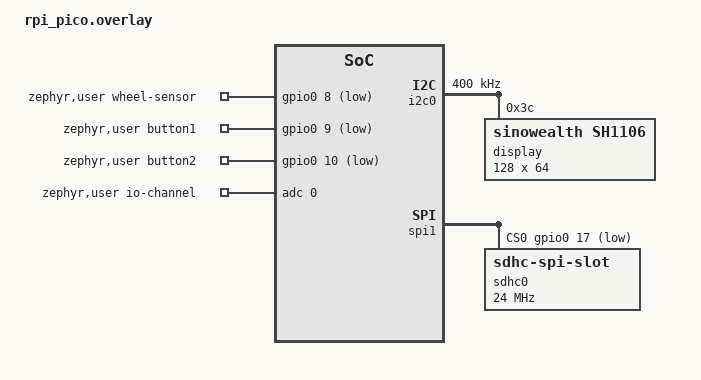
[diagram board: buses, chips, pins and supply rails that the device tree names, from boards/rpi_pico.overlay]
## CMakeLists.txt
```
cmake_minimum_required(VERSION 3.20.0)

find_package(Zephyr REQUIRED HINTS $ENV{ZEPHYR_BASE})
project(wheel_sensor)

# Include directories
target_include_directories(app PRIVATE include src)

# Main application and module sources
target_sources(app PRIVATE
    src/main.c
    src/app.c
    src/wheel_sensor.c
    src/button.c
    src/battery.c
    src/speed_calculator.c
    src/display_output.c
    src/console_output.c
    src/storage.c
)

# Simulation shell (optional)
if(CONFIG_APP_SIMULATION)
    target_sources(app PRIVATE src/sim_shell.c)
endif()
```

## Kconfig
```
menu "Application Configuration"

config DISPLAY_ENABLED
	bool "Enable OLED display support (SH1106)"
	default y
	imply I2C
	imply DISPLAY
	imply SSD1306
	imply CHARACTER_FRAMEBUFFER
	help
		Enable support for SH1106 OLED display over I2C.
		When enabled, the display driver and related functionality are included.
		When disabled, all display-related code is excluded.

config SD_CARD_ENABLED
	bool "Enable SD card storage via SPI"
	default y
	imply SPI
	imply SDHC
	imply SDMMC_STACK
	imply DISK_ACCESS
	imply FILE_SYSTEM
	imply FAT_FILESYSTEM_ELM
	help
		Enable support for SD card storage over SPI.
		When enabled, the SD card driver and filesystem support are included.
		When disabled, all SD card-related code and dependencies are excluded.

config APP_SIMULATION
    bool "Enable shell commands to drive simulated peripherals"
    depends on GPIO_EMUL || ADC_EMUL
    help
      Adds 'sim' shell commands to manually toggle the reed switch,
      simulate a button press, and set a fake battery voltage while
      running the app on native_sim.

config LOG_LEVEL_GLOBAL
	int "Global application log level"
	default 3
	range 0 4
	help
		Sets the default log level for all application modules.
		0 - None, 1 - Error, 2 - Warning, 3 - Info, 4 - Debug
		Individual modules can still use LOG_LEVEL_SET() to override.

endmenu

source "Kconfig.zephyr"
```

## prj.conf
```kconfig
# GPIO is required to read the reed switch / Hall sensor
CONFIG_GPIO=y

# ADC for battery voltage monitoring
CONFIG_ADC=y

# Console output so we can see revolution/speed data over USB-UART
CONFIG_PRINTK=y
CONFIG_CONSOLE=y
CONFIG_SERIAL=y

# SPI for SD card (enabled by SD_CARD_ENABLED config)
CONFIG_EMUL=y
CONFIG_HEAP_MEM_POOL_SIZE=256

# Settings subsystem for persistent storage
CONFIG_SETTINGS=y
CONFIG_SETTINGS_RUNTIME=y
CONFIG_FLASH=y
CONFIG_FLASH_MAP=y
CONFIG_NVS=y

# Logging configuration
CONFIG_LOG=y
```

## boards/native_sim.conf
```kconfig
CONFIG_GPIO=y
CONFIG_GPIO_EMUL=y
CONFIG_ADC=y
CONFIG_ADC_EMUL=y
CONFIG_CONSOLE=y
CONFIG_SHELL=y
CONFIG_SHELL_BACKEND_SERIAL=y

# Disable display support for native_sim
CONFIG_DISPLAY_ENABLED=n
CONFIG_DISPLAY=n

CONFIG_APP_SIMULATION=y
```

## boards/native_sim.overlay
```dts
/*
 * Simulation overlay mapping to the same paths as rpi_pico.overlay
 * Uses zephyr,user node with the same property names
 */
/ {
	zephyr,user {
		/* Wheel sensor - maps to reed0 in sim_inputs */
		wheel-sensor-gpios = <&gpio0 1 (GPIO_ACTIVE_LOW)>;
		/* Buttons - map to button0 in sim_inputs */
		button1-gpios = <&gpio0 0 (GPIO_ACTIVE_LOW)>;
		button2-gpios = <&gpio0 2 (GPIO_ACTIVE_LOW)>;
		/* Battery ADC channel - maps to channel@0 in adc0 */
		io-channels = <&adc0 0>;
	};
};

/* native_sim.dts already provides gpio0 as a gpio_emul controller
   and usually an adc0 as zephyr,adc-emul — check your Zephyr version's
   boards/native/native_sim/native_sim.dts. If adc0 isn't already there,
   add it yourself here instead of just configuring the channel below. */
&adc0 {
	#address-cells = <1>;
	#size-cells = <0>;

	channel@0 {
		reg = <0>;
		zephyr,gain = "ADC_GAIN_1";
		zephyr,reference = "ADC_REF_INTERNAL";
		zephyr,vref-mv = <3300>;
		zephyr,resolution = <12>;
		zephyr,acquisition-time = <ADC_ACQ_TIME_DEFAULT>;
	};
};
```

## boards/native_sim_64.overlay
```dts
/*
 * native_sim 64-bit variant overlay.
 * Keep the native simulator free of display emulation and provide the
 * same user-facing GPIO and ADC nodes the application expects.
 */
/ {
	zephyr,user {
		/* Wheel sensor - maps to reed0 in sim_inputs */
		wheel-sensor-gpios = <&gpio0 1 (GPIO_ACTIVE_LOW)>;
		/* Buttons - map to button0 in sim_inputs */
		button1-gpios = <&gpio0 0 (GPIO_ACTIVE_LOW)>;
		button2-gpios = <&gpio0 2 (GPIO_ACTIVE_LOW)>;
		/* Battery ADC channel - maps to channel@0 in adc0 */
		io-channels = <&adc0 0>;
	};

	chosen {
		/delete-property/ zephyr,display;
	};
};

&sdl_dc {
	status = "disabled";
};

&spi0 {
	sdhc0: sdhc@0 {
		compatible = "zephyr,sdhc-spi-slot";
		reg = <0>;
		status = "okay";
		spi-max-frequency = <24000000>;

		mmc {
			compatible = "zephyr,sdmmc-disk";
			disk-name = "SD";
			status = "okay";
		};
	};
};

&adc0 {
	#address-cells = <1>;
	#size-cells = <0>;

	channel@0 {
		reg = <0>;
		zephyr,gain = "ADC_GAIN_1";
		zephyr,reference = "ADC_REF_INTERNAL";
		zephyr,vref-mv = <3300>;
		zephyr,resolution = <12>;
		zephyr,acquisition-time = <ADC_ACQ_TIME_DEFAULT>;
	};
};
```

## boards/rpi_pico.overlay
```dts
/*
 * Wire the reed switch / Hall sensor to GPIO pin 16.
 * One leg of the switch/sensor goes to this pin, the other to GND.
 * GPIO_PULL_UP keeps the line high when open; the switch/sensor pulls
 * it low (ACTIVE_LOW) when the magnet passes.
 *
 * Change the pin number below to match your wiring if needed.
 */
/ {
	zephyr,user {
		wheel-sensor-gpios = <&gpio0 8 (GPIO_ACTIVE_LOW | GPIO_PULL_UP)>;
		button1-gpios = <&gpio0 9 (GPIO_ACTIVE_LOW | GPIO_PULL_UP)>;
		button2-gpios = <&gpio0 10 (GPIO_ACTIVE_LOW | GPIO_PULL_UP)>;
		/* Battery voltage monitoring via ADC0 (GPIO26) */
		io-channels = <&adc 0>;
	};

	chosen {
		zephyr,display = &display;
	};
};

/* Enable I2C for SH1106 display */
&i2c0 {
	status = "okay";
	clock-frequency = <400000>;

	display: sh1106@3c {
		compatible = "sinowealth,sh1106";
		reg = <0x3c>;
		width = <128>;
		height = <64>;
		segment-offset = <0>;
		page-offset = <0>;
		display-offset = <0>;
		multiplex-ratio = <63>;
		segment-remap;
		com-invdir;
		prechargep = <0x22>;
	};
};

/* Add storage partition for NVS settings to existing flash0 partitions */
&flash0 {
	partitions {
		compatible = "fixed-partitions";
        #address-cells = <1>;
        #size-cells = <1>;
			/* Storage partition for NVS settings - 16KB at 128KB offset from flash start */
		storage_partition: partition@20000 {
			label = "storage";
			reg = <0x00020000 0x00004000>;
		};
	};
};

&spi1 {
        status = "okay";
        cs-gpios = <&gpio0 17 GPIO_ACTIVE_LOW>;

        sdhc0: sdhc@0 {
                compatible = "zephyr,sdhc-spi-slot";
                reg = <0>;
                status = "okay";
                mmc {
                    compatible = "zephyr,sdmmc-disk";
                    disk-name = "SD";
                    status = "okay";
                };
                spi-max-frequency = <24000000>;
        };
};
```

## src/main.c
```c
/*
 * main.c - Application entry point
 *
 * Simply calls the modular application implementation.
 *
 * @implements REQ-SW-001
 */

#include <app.h>

/**
 * @brief Application main entry point
 * @implements REQ-SW-001
 * @return Application exit code
 */
int main(void)
{
	return app_run();
}
```

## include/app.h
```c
/*
 * app.h - Main application header for wheel sensor speedometer
 *
 * Defines shared data structures, constants, and constants.
 * All modules should include this header for common types.
 *
 * Module-specific interfaces are in their respective header files:
 * - wheel_sensor.h
 * - button.h
 * - battery.h
 * - speed_calculator.h
 * - display_output.h
 * - console_output.h
 * - storage.h
 */

#ifndef APP_H
#define APP_H

#include <zephyr/kernel.h>
#include <zephyr/sys/atomic.h>
#include <stdbool.h>
#include <stdint.h>

/* =========================================================================
 * CONSTANTS
 * ========================================================================= */

/* Wheel configuration limits */
#define MIN_WHEEL_DIAMETER_CM    10
#define MAX_WHEEL_DIAMETER_CM    100
#define DEFAULT_WHEEL_DIAMETER_CM 66

/* Timing constants */
#define DEBOUNCE_MS              50
#define REPORT_INTERVAL_MS       1000
#define MODE_SWITCH_DELAY_MS     500
#define BATTERY_SAMPLE_INTERVAL_S 60

/* Battery monitoring constants */
#define BATTERY_MIN_V            2.0f   /* Voltage at 0% (2x AA depleted) */
#define BATTERY_MAX_V            3.0f   /* Voltage at 100% (2x AA fresh) */
#define VOLTAGE_DIVIDER_RATIO    (3.0f / 2.0f)  /* V_battery = V_adc * (R1+R2)/R2 */

/* Buffer sizes */
#define LOG_BUFFER_SIZE          256
#define DISPLAY_LINE_SIZE        32

/* =========================================================================
 * DATA STRUCTURES
 * ========================================================================= */

/* Wheel sensor state - shared between ISR and main thread */
struct wheel_sensor_state {
	atomic_t revolution_count;
	volatile int64_t last_trigger_ms;
};

/* Button state - shared between ISR and main thread */
struct button_state {
	volatile int64_t last_press_ms[2];
	volatile bool in_settings_mode;
	volatile bool save_wheel_diameter_pending;
	int64_t previous_press_time[2];
	/* Flags for deferred printing (set in ISR, cleared in main thread) */
	volatile bool settings_mode_changed;
	volatile bool diameter_changed;
	int diameter_value;
};

/* Wheel configuration */
struct wheel_config {
	int diameter_cm;
};

/* Battery state */
struct battery_state {
	int percentage;
	float voltage;
	bool valid;
};

/* Runtime tracking state (main thread only) */
struct runtime_state {
	uint32_t last_count;
	uint32_t total_distance_m;
	float last_speed_kmh;
};

/* =========================================================================
 * INLINE ACCESSORS
 * ========================================================================= */

/**
 * @brief Check if in settings mode
 * @param button_state Pointer to button state structure
 * @return true if in settings mode
 */
static inline bool button_in_settings_mode(const struct button_state *button_state)
{
	return button_state->in_settings_mode;
}

/**
 * @brief Check if wheel diameter needs saving
 * @param button_state Pointer to button state structure
 * @return true if pending save
 */
static inline bool button_save_pending(const struct button_state *button_state)
{
	return button_state->save_wheel_diameter_pending;
}

/**
 * @brief Clear save pending flag
 * @param button_state Pointer to button state structure
 */
static inline void button_clear_save_pending(struct button_state *button_state)
{
	button_state->save_wheel_diameter_pending = false;
}

/**
 * @brief Application entry point
 */
int app_run(void);

#endif /* APP_H */
```

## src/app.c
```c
/*
 * app.c - Main application with modular architecture
 *
 * Coordinates all modules to implement the wheel sensor speedometer.
 *
 * @implements REQ-SW-001, REQ-SW-002, REQ-SW-003, REQ-SW-004, REQ-SW-005, REQ-SW-006, REQ-SW-007, REQ-SW-008
 */

#include <app.h>
#include <wheel_sensor.h>
#include <button.h>
#include <battery.h>
#include <speed_calculator.h>
#include <display_output.h>
#include <console_output.h>
#include <storage.h>

#include <zephyr/kernel.h>
#include <zephyr/sys/printk.h>
#include <zephyr/sys/util.h>
#include <zephyr/logging/log.h>

LOG_MODULE_REGISTER(app);

/* Global state instances */
static struct wheel_sensor_state wheel_sensor_state = {
	.revolution_count = ATOMIC_INIT(0),
	.last_trigger_ms = 0,
};

static struct button_state button_state = {
	.last_press_ms = {0, 0},
	.in_settings_mode = false,
	.save_wheel_diameter_pending = false,
	.previous_press_time = {0, 0},
	.settings_mode_changed = false,
	.diameter_changed = false,
	.diameter_value = DEFAULT_WHEEL_DIAMETER_CM,
};

static struct wheel_config wheel_config = {
	.diameter_cm = DEFAULT_WHEEL_DIAMETER_CM,
};

static struct runtime_state runtime_state = {
	.last_count = 0U,
	.total_distance_m = 0U,
	.last_speed_kmh = 0.0f,
};

static struct battery_state battery_state = {
	.percentage = -1,
	.voltage = 0.0f,
	.valid = false,
};

static void app_state_work_handler(struct k_work *work);

K_WORK_DEFINE(app_state_work, app_state_work_handler);

/**
 * @brief Work handler for deferred state updates
 * @implements REQ-SW-003, REQ-SW-601
 * @param work Work item (unused)
 */
static void app_state_work_handler(struct k_work *work)
{
	ARG_UNUSED(work);

	if (button_save_pending(&button_state)) {
		button_clear_save_pending(&button_state);
		storage_save_wheel_diameter(&wheel_config);
	}

	if (display_is_available()) {
		display_render(&button_state, &wheel_config, &runtime_state, &battery_state);
	}
}

/**
 * @brief Queue deferred state update
 * @implements REQ-SW-601
 */
static void queue_app_state_update(void)
{
	k_work_submit(&app_state_work);
}

/**
 * @brief Main application entry point
 * @implements REQ-SW-001, REQ-SW-002, REQ-SW-003, REQ-SW-004, REQ-SW-005, REQ-SW-006, REQ-SW-007, REQ-SW-008
 * @return Application exit code
 */
int app_run(void)
{
	int ret;

	/* Initialize storage/NVS first so settings can be loaded */
	ret = storage_init(&wheel_config);
	if (ret < 0) {
		LOG_ERR("Storage initialization failed: %d", -ret);
		return ret;
	}

	console_print_init(wheel_config.diameter_cm);

	/* Initialize display */
	ret = display_init();
	if (ret < 0) {
		LOG_WRN("Display initialization failed: %d, continuing without display", -ret);
	} else {
		queue_app_state_update();
	}

	/* Initialize SD card for logging */
	ret = storage_sd_init();
	if (ret < 0) {
		LOG_WRN("SD card initialization failed: %d, continuing without SD card", -ret);
	} else {
		ret = storage_log_open();
		if (ret < 0) {
			LOG_WRN("Failed to open log file: %d, continuing without SD card logging", -ret);
		} else {
			LOG_INF("SD card logging initialized");
		}
	}

	/* Initialize battery monitoring */
	ret = battery_init();
	if (ret < 0) {
		LOG_ERR("Battery initialization failed: %d", -ret);
		return ret;
	}

	/* Initialize wheel sensor */
	ret = wheel_sensor_init(&wheel_sensor_state);
	if (ret < 0) {
		LOG_ERR("Wheel sensor initialization failed: %d", -ret);
		return ret;
	}

	/* Initialize buttons */
	button_set_wheel_config(&wheel_config);
	ret = button_init(&button_state);
	if (ret < 0) {
		LOG_WRN("Button initialization failed: %d, continuing without buttons", -ret);
	}

	uint32_t battery_sample_counter = 0;

	while (1) {
		k_msleep(REPORT_INTERVAL_MS);

		/* Sample battery voltage periodically */
		battery_sample_counter++;
		if (battery_sample_counter >= BATTERY_SAMPLE_INTERVAL_S) {
			int battery_ret = battery_read(&battery_state);
			if (battery_ret < 0) {
				LOG_ERR("Battery read failed: %d", battery_ret);
			} else {
				console_print_battery(battery_state.percentage, battery_state.voltage);
			}
			battery_sample_counter = 0;
		}

		/* Handle deferred button press messages (from ISR) */
		if (button_state.settings_mode_changed) {
			button_state.settings_mode_changed = false;
			if (button_state.in_settings_mode) {
				LOG_INF("Entering settings mode. Current diameter: %d cm",
					button_state.diameter_value);
			} else {
				LOG_INF("Exiting settings mode. Wheel diameter set to: %d cm",
					button_state.diameter_value);
			}
		}
		if (button_state.diameter_changed) {
			button_state.diameter_changed = false;
			LOG_INF("Wheel diameter: %d cm", button_state.diameter_value);
		}

		/* If in settings mode, skip speed calculation but still update display */
		if (button_in_settings_mode(&button_state)) {
			queue_app_state_update();
			continue;
		}

		/* Get current revolution count */
		uint32_t current_count = wheel_sensor_get_count(&wheel_sensor_state);

		/* Calculate speed and distance */
		speed_calculator_update(
			current_count, runtime_state.last_count,
			wheel_config.diameter_cm, REPORT_INTERVAL_MS,
			&runtime_state.total_distance_m, &runtime_state.last_speed_kmh);
		runtime_state.last_count = current_count;

		/* Print status to console */
		console_print_status(
			current_count, runtime_state.last_speed_kmh,
			runtime_state.total_distance_m, wheel_config.diameter_cm);

		/* Log to SD card if available */
		if (storage_log_available()) {
			char log_msg[LOG_BUFFER_SIZE];
			snprintk(log_msg, sizeof(log_msg),
				"[%lld] revs=%u, speed=%.1f km/h, distance=%u m, diameter=%d cm\n",
				k_uptime_get(), current_count, (double)runtime_state.last_speed_kmh,
				runtime_state.total_distance_m, wheel_config.diameter_cm);
			storage_log_write(log_msg);
		}

		queue_app_state_update();
	}

	return 0;
}
```

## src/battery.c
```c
/*
 * battery.c - Battery monitoring module
 *
 * Handles ADC-based battery voltage monitoring and percentage calculation.
 *
 * @implements REQ-HW-040, REQ-HW-041, REQ-HW-042, REQ-SW-401, REQ-SW-402, REQ-SW-403, REQ-SW-404, REQ-SW-405, REQ-SW-406, REQ-SW-407, REQ-SW-408, REQ-SW-409, REQ-SW-410
 * @tests tests/battery/src/test_battery.c
 */

#include <battery.h>
#include <zephyr/kernel.h>
#include <zephyr/drivers/adc.h>
#include <zephyr/logging/log.h>

LOG_MODULE_REGISTER(battery);

/* Devicetree configuration */
#define USER_NODE DT_PATH(zephyr_user)
static const struct adc_dt_spec battery_adc =
	ADC_DT_SPEC_GET_BY_IDX(USER_NODE, 0);

/**
 * @brief Initialize battery ADC
 * @implements REQ-SW-401
 * @return 0 on success, negative errno on failure
 */
int battery_init(void)
{
	if (!device_is_ready(battery_adc.dev)) {
		return -ENODEV;
	}
	return 0;
}

/**
 * @brief Read battery voltage and update state
 *
 * Battery must be already initialized via a successful call to
 * battery_init() prior to calling this function.
 *
 * @implements REQ-SW-401, REQ-SW-402, REQ-SW-410
 * @param battery_state Pointer to battery state structure to update
 * @return 0 on success, negative errno on failure
 */
int battery_read(struct battery_state *battery_state)
{
	int16_t adc_value;
	struct adc_sequence sequence = {
		.channels = BIT(battery_adc.channel_id),
		.buffer = &adc_value,
		.buffer_size = sizeof(adc_value),
		.resolution = 12,
	};

	int ret = adc_read(battery_adc.dev, &sequence);
	if (ret < 0) {
		LOG_ERR("Battery ADC read error: %d", ret);
		return ret;
	}

	float battery_voltage = battery_adc_to_voltage(adc_value);
	int percentage = battery_voltage_to_percentage(battery_voltage);

	battery_state->voltage = battery_voltage;
	battery_state->percentage = percentage;
	battery_state->valid = true;

	return 0;
}

/**
 * @brief Convert ADC value to battery voltage
 * @implements REQ-SW-403, REQ-SW-404, REQ-SW-405
 * @param adc_value Raw ADC value (12-bit)
 * @return Battery voltage in volts
 */
float battery_adc_to_voltage(int16_t adc_value)
{
	/* Convert ADC value to voltage (12-bit ADC, 3.3V reference)
	 * NOTE: The 3.3V reference is hardcoded. The actual RP2040 ADC reference
	 * can vary by +/- 1-2% which will cause a systematic offset in battery
	 * voltage readings. For more accurate readings, consider reading the
	 * actual Vref from ADC calibration data. */
	float adc_voltage = (adc_value * 3.3f) / 4095.0f;

	/* Apply voltage divider ratio: V_battery = V_adc * (R1+R2)/R2 */
	return adc_voltage * VOLTAGE_DIVIDER_RATIO;
}

/**
 * @brief Convert battery voltage to percentage
 * @implements REQ-SW-406, REQ-SW-407, REQ-SW-408, REQ-SW-409
 * @param voltage Battery voltage in volts
 * @return Percentage (0-100)
 */
int battery_voltage_to_percentage(float voltage)
{
	/* Linear approximation for alkaline 2xAA */
	int percentage = (int)((voltage - BATTERY_MIN_V) /
			(BATTERY_MAX_V - BATTERY_MIN_V) * 100.0f);
	return CLAMP(percentage, 0, 100);
}
```

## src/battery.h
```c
/*
 * battery.h - Battery monitoring module interface
 *
 * Handles ADC-based battery voltage monitoring and percentage calculation.
 */

#ifndef BATTERY_H
#define BATTERY_H

#include "app.h"
#include <zephyr/device.h>
#include <zephyr/devicetree.h>
#include <zephyr/drivers/adc.h>
#include <stdbool.h>

/**
 * @brief Initialize battery ADC
 * @return 0 on success, negative errno on failure
 */
__must_check int battery_init(void);

/**
 * @brief Read battery voltage and update state
 * @param battery_state Pointer to battery state structure to update
 * @return 0 on success, negative errno on failure
 */
__must_check int battery_read(struct battery_state *battery_state);

/**
 * @brief Convert ADC value to battery voltage
 * @param adc_value Raw ADC value (12-bit)
 * @return Battery voltage in volts
 */
float battery_adc_to_voltage(int16_t adc_value);

/**
 * @brief Convert battery voltage to percentage
 * @param voltage Battery voltage in volts
 * @return Percentage (0-100)
 */
int battery_voltage_to_percentage(float voltage);

#endif /* BATTERY_H */
```

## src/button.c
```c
/*
 * button.c - Button input module
 *
 * Handles button input with debouncing and settings mode management.
 * Button 1: Double-press toggles settings mode, single press increments diameter
 * Button 2: Single press decrements diameter in settings mode
 *
 * @implements REQ-HW-020, REQ-HW-021, REQ-HW-022, REQ-HW-023, REQ-SW-301, REQ-SW-302, REQ-SW-303, REQ-SW-304, REQ-SW-305, REQ-SW-306, REQ-SW-307, REQ-SW-308, REQ-SW-309, REQ-SW-310, REQ-SW-311
 */

#include <button.h>
#include <app.h>
#include <zephyr/kernel.h>
#include <zephyr/drivers/gpio.h>
#include <zephyr/sys/printk.h>
#include <zephyr/sys/util.h>
#include <zephyr/sys/check.h>

/* Devicetree configuration */
#define USER_NODE DT_PATH(zephyr_user)
static const struct gpio_dt_spec button1 =
	GPIO_DT_SPEC_GET(USER_NODE, button1_gpios);
static const struct gpio_dt_spec button2 =
	GPIO_DT_SPEC_GET(USER_NODE, button2_gpios);

static struct button_state *button_state_ptr = NULL;
static struct wheel_config *wheel_config_ptr = NULL;

/* NOTE: button_state_ptr and wheel_config_ptr are set by button_init() and
 * button_set_wheel_config() respectively. There is a small race condition window
 * between these two calls in app.c where button_set_wheel_config() is called
 * before button_init(). If a button interrupt fires during this window,
 * __ASSERT_NO_MSG(wheel_config_ptr != NULL) will trigger. In practice this is
 * unlikely as initialization is fast, but for robustness consider using a
 * single initialization function that takes all required pointers. */

/* Button callback data structure with user data */
struct button_cb_data {
	struct gpio_callback callback;
	int button_idx;
};
static struct button_cb_data button_cb_data[2];

/* Internal processing function */
/**
 * @brief Internal processing function for button presses
 * @implements REQ-SW-301, REQ-SW-302, REQ-SW-303, REQ-SW-304, REQ-SW-305, REQ-SW-306, REQ-SW-307, REQ-SW-308, REQ-SW-309, REQ-SW-310, REQ-SW-311
 * @param button_idx Button index (0 for button1, 1 for button2)
 */
static void process_button_press(int button_idx)
{
	/* Use __ASSERT_NO_MSG for NULL checks in ISR context */
	__ASSERT_NO_MSG(button_state_ptr != NULL);
	__ASSERT_NO_MSG(wheel_config_ptr != NULL);

	int64_t now = k_uptime_get();

	/* Debounce check */
	if ((now - button_state_ptr->last_press_ms[button_idx]) < DEBOUNCE_MS) {
		return;
	}
	button_state_ptr->last_press_ms[button_idx] = now;

	if (button_idx == 0) {
		/* Button 1: double press toggles settings mode; single press increments diameter */
		if ((now - button_state_ptr->previous_press_time[button_idx]) < MODE_SWITCH_DELAY_MS) {
			button_state_ptr->in_settings_mode = !button_state_ptr->in_settings_mode;
			button_state_ptr->settings_mode_changed = true;
			button_state_ptr->diameter_value = wheel_config_ptr->diameter_cm;
			if (!button_state_ptr->in_settings_mode) {
				button_state_ptr->save_wheel_diameter_pending = true;
			}
		} else {
			if (button_state_ptr->in_settings_mode) {
				wheel_config_ptr->diameter_cm =
					MIN(wheel_config_ptr->diameter_cm + 1, MAX_WHEEL_DIAMETER_CM);
				button_state_ptr->diameter_changed = true;
				button_state_ptr->diameter_value = wheel_config_ptr->diameter_cm;
			}
		}
		button_state_ptr->previous_press_time[button_idx] = now;
	} else {
		/* Button 2: single press decrements diameter in settings mode */
		if (button_state_ptr->in_settings_mode) {
			wheel_config_ptr->diameter_cm =
				MAX(wheel_config_ptr->diameter_cm - 1, MIN_WHEEL_DIAMETER_CM);
			button_state_ptr->diameter_changed = true;
			button_state_ptr->diameter_value = wheel_config_ptr->diameter_cm;
		}
	}
}

/**
 * @brief Unified callback for all buttons
 * @implements REQ-SW-301, REQ-SW-302
 * @param dev Device pointer (unused)
 * @param cb Callback pointer
 * @param pins Triggered pins (unused)
 */
/* Unified callback for all buttons */
static void button_pressed(const struct device *dev, struct gpio_callback *cb, uint32_t pins)
{
	ARG_UNUSED(dev);
	ARG_UNUSED(pins);
	struct button_cb_data *data = CONTAINER_OF(cb, struct button_cb_data, callback);
	process_button_press(data->button_idx);
}

/**
 * @brief Initialize button GPIOs and interrupts
 * @implements REQ-SW-301, REQ-SW-302
 * @param button_state Pointer to button state structure
 * @return 0 on success, negative errno on failure
 */
int button_init(struct button_state *button_state)
{
	int ret;

	button_state_ptr = button_state;

	/* Initialize button state */
	button_state->last_press_ms[0] = 0;
	button_state->last_press_ms[1] = 0;
	button_state->in_settings_mode = false;
	button_state->save_wheel_diameter_pending = false;
	button_state->previous_press_time[0] = 0;
	button_state->previous_press_time[1] = 0;

	if (!device_is_ready(button1.port) || !device_is_ready(button2.port)) {
		return -ENODEV;
	}

	/* Configure button 1 */
	ret = gpio_pin_configure_dt(&button1, GPIO_INPUT);
	if (ret != 0) {
		return ret;
	}

	ret = gpio_pin_interrupt_configure_dt(&button1, GPIO_INT_EDGE_TO_ACTIVE);
	if (ret != 0) {
		return ret;
	}

	button_cb_data[0].button_idx = 0;
	gpio_init_callback(&button_cb_data[0].callback, button_pressed, BIT(button1.pin));
	gpio_add_callback(button1.port, &button_cb_data[0].callback);

	/* Configure button 2 */
	ret = gpio_pin_configure_dt(&button2, GPIO_INPUT);
	if (ret != 0) {
		return ret;
	}

	ret = gpio_pin_interrupt_configure_dt(&button2, GPIO_INT_EDGE_TO_ACTIVE);
	if (ret != 0) {
		return ret;
	}

	button_cb_data[1].button_idx = 1;
	gpio_init_callback(&button_cb_data[1].callback, button_pressed, BIT(button2.pin));
	gpio_add_callback(button2.port, &button_cb_data[1].callback);

	return 0;
}

/**
 * @brief Set wheel config pointer for button callbacks
 * @implements REQ-SW-303
 * @param wheel_config Pointer to wheel configuration
 */
void button_set_wheel_config(struct wheel_config *wheel_config)
{
	wheel_config_ptr = wheel_config;
}
```

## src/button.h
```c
/*
 * button.h - Button input module interface
 *
 * Handles button input with debouncing and settings mode management.
 */

#ifndef BUTTON_H
#define BUTTON_H

#include <app.h>
#include <zephyr/device.h>
#include <zephyr/devicetree.h>
#include <zephyr/drivers/gpio.h>

/**
 * @brief Initialize button GPIOs and interrupts
 * @param button_state Pointer to button state structure
 * @return 0 on success, negative errno on failure
 */
int button_init(struct button_state *button_state);

/**
 * @brief Set wheel config pointer for button callbacks
 * @param wheel_config Pointer to wheel configuration
 */
void button_set_wheel_config(struct wheel_config *wheel_config);

/**
 * @brief Get button count
 * @return Number of buttons (currently 2)
 */
static inline int button_count(void)
{
	return 2;
}

#endif /* BUTTON_H */
```

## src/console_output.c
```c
/*
 * console_output.c - Console output module
 *
 * Handles all console/printk output for the application.
 *
 * @implements REQ-SW-701, REQ-SW-702, REQ-SW-703, REQ-SW-704, REQ-SW-705, REQ-SW-706, REQ-SW-707, REQ-SW-708
 */

#include <console_output.h>
#include <zephyr/sys/printk.h>
#include <zephyr/logging/log.h>

LOG_MODULE_REGISTER(console);

/**
 * @brief Print status information to console
 * @implements REQ-SW-701, REQ-SW-702
 * @param current_count Current revolution count
 * @param speed_kmh Current speed in km/h
 * @param total_distance_m Total distance in meters
 * @param wheel_diameter_cm Wheel diameter in centimeters
 */
void console_print_status(uint32_t current_count, float speed_kmh,
		uint32_t total_distance_m, int wheel_diameter_cm)
{
	unsigned int speed_frac = (unsigned int)((speed_kmh - (int)speed_kmh) * 10.0f);
	if (speed_frac > 9U) {
		speed_frac = 9U;
	}

	LOG_DBG("revs=%u  speed=%d.%01u km/h  distance=%u m  diameter=%d cm",
		current_count,
		(int)speed_kmh,
		speed_frac,
		total_distance_m,
		wheel_diameter_cm);
}

/**
 * @brief Print settings mode information to console
 * @implements REQ-SW-706
 * @param in_settings_mode True if entering settings mode, false if exiting
 * @param diameter_cm Current wheel diameter in centimeters
 */
void console_print_settings_mode(bool in_settings_mode, int diameter_cm)
{
	if (in_settings_mode) {
		LOG_INF("Entering settings mode. Current diameter: %d cm", diameter_cm);
	} else {
		LOG_INF("Exiting settings mode. Wheel diameter set to: %d cm", diameter_cm);
	}
}

/**
 * @brief Print wheel diameter change to console
 * @implements REQ-SW-707
 * @param diameter_cm Current wheel diameter in centimeters
 */
void console_print_diameter(int diameter_cm)
{
	LOG_INF("Wheel diameter: %d cm", diameter_cm);
}

/**
 * @brief Print battery status to console
 * @implements REQ-SW-708
 * @param percentage Battery percentage
 * @param voltage Battery voltage in volts
 */
void console_print_battery(int percentage, float voltage)
{
	LOG_INF("Battery: %d%% (%.2fV)", percentage, (double)voltage);
}

/**
 * @brief Print initialization message to console
 * @implements REQ-SW-705
 * @param diameter_cm Current wheel diameter in centimeters
 */
void console_print_init(int diameter_cm)
{
	LOG_INF("Wheel diameter: %d cm", diameter_cm);
	LOG_INF("Wheel sensor ready, waiting for revolutions...");
	LOG_INF("Press button 1 twice quickly to enter settings mode");
}
```

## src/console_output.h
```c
/*
 * console_output.h - Console output module interface
 *
 * Handles all console/printk output for the application.
 */

#ifndef CONSOLE_OUTPUT_H
#define CONSOLE_OUTPUT_H

#include <stdint.h>
#include <stdbool.h>

/**
 * @brief Print status to console
 * @param current_count Current revolution count
 * @param speed_kmh Current speed in km/h
 * @param total_distance_m Total distance in meters
 * @param wheel_diameter_cm Wheel diameter in centimeters
 */
void console_print_status(uint32_t current_count, float speed_kmh,
		uint32_t total_distance_m, int wheel_diameter_cm);

/**
 * @brief Print settings mode status
 * @param in_settings_mode true if entering settings mode
 * @param diameter_cm Current wheel diameter
 */
void console_print_settings_mode(bool in_settings_mode, int diameter_cm);

/**
 * @brief Print wheel diameter update
 * @param diameter_cm New wheel diameter
 */
void console_print_diameter(int diameter_cm);

/**
 * @brief Print battery status
 * @param percentage Battery percentage
 * @param voltage Battery voltage
 */
void console_print_battery(int percentage, float voltage);

/**
 * @brief Print initialization message
 * @param diameter_cm Wheel diameter
 */
void console_print_init(int diameter_cm);

#endif /* CONSOLE_OUTPUT_H */
```

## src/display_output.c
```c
/*
 * display_output.c - Display output module
 *
 * Handles rendering of application state to the OLED display (SH1106).
 *
 * @implements REQ-HW-030, REQ-HW-031, REQ-SW-501, REQ-SW-502, REQ-SW-503, REQ-SW-504, REQ-SW-505, REQ-SW-506, REQ-SW-507, REQ-SW-508, REQ-SW-509
 * @tests tests/display/src/test_display.c
 */

#include <display_output.h>
#include <zephyr/display/cfb.h>
#include <zephyr/sys/printk.h>
#include <zephyr/device.h>
#include <zephyr/devicetree.h>
#include <zephyr/logging/log.h>

LOG_MODULE_REGISTER(display);

#if IS_ENABLED(CONFIG_DISPLAY) && IS_ENABLED(CONFIG_CHARACTER_FRAMEBUFFER) && \
	DT_HAS_CHOSEN(zephyr_display)

static const struct device *display_dev;
static uint8_t display_font_height;
static bool display_initialized = false;

/**
 * @brief Initialize display
 * @implements REQ-SW-508, REQ-SW-509
 * @return 0 on success, negative errno on failure
 */
int display_init(void)
{
	int ret;
	uint8_t font_width;

	display_dev = DEVICE_DT_GET(DT_CHOSEN(zephyr_display));
	if (!device_is_ready(display_dev)) {
		LOG_WRN("Display device not ready");
		return -ENODEV;
	}

	ret = display_set_pixel_format(display_dev, PIXEL_FORMAT_MONO10);
	if (ret < 0) {
		ret = display_set_pixel_format(display_dev, PIXEL_FORMAT_MONO01);
	}
	if (ret < 0) {
		LOG_WRN("Display does not support mono pixel formats: %d", ret);
		return ret;
	}

	ret = cfb_framebuffer_init(display_dev);
	if (ret < 0) {
		LOG_WRN("Failed to initialize display framebuffer: %d", ret);
		return ret;
	}

	ret = cfb_framebuffer_set_font(display_dev, 0);
	if (ret < 0) {
		LOG_WRN("Failed to select default display font: %d", ret);
		return ret;
	}

	ret = cfb_get_font_size(display_dev, 0, &font_width, &display_font_height);
	if (ret < 0 || display_font_height == 0U) {
		display_font_height = 8U;
	}

	ret = display_blanking_off(display_dev);
	if (ret < 0 && ret != -ENOSYS) {
		LOG_WRN("Failed to unblank display: %d", ret);
	}

	display_initialized = true;
	return 0;
}

static void display_print_lines(const char *line1, const char *line2,
			const char *line3, const char *line4)
{
	int y = 0;

	if (display_dev == NULL || !display_initialized) {
		return;
	}

	cfb_framebuffer_clear(display_dev, false);

	if (line1 != NULL) {
		cfb_print(display_dev, line1, 0, y);
	}
	y += display_font_height;

	if (line2 != NULL) {
		cfb_print(display_dev, line2, 0, y);
	}
	y += display_font_height;

	if (line3 != NULL) {
		cfb_print(display_dev, line3, 0, y);
	}
	y += display_font_height;

	if (line4 != NULL) {
		cfb_print(display_dev, line4, 0, y);
	}

	cfb_framebuffer_finalize(display_dev);
}

/**
 * @brief Render application state to display
 * @implements REQ-SW-501, REQ-SW-502, REQ-SW-503, REQ-SW-504, REQ-SW-505, REQ-SW-506, REQ-SW-507
 * @param button_state Pointer to button state
 * @param wheel_config Pointer to wheel configuration
 * @param runtime_state Pointer to runtime state
 * @param battery_state Pointer to battery state
 */
void display_render(const struct button_state *button_state,
		const struct wheel_config *wheel_config,
		const struct runtime_state *runtime_state,
		const struct battery_state *battery_state)
{
	char line1[DISPLAY_LINE_SIZE];
	char line2[DISPLAY_LINE_SIZE];
	char line3[DISPLAY_LINE_SIZE];
	char line4[DISPLAY_LINE_SIZE];
	int speed_whole;
	unsigned int speed_frac;

	if (!display_initialized || display_dev == NULL) {
		return;
	}

	if (button_state->in_settings_mode) {
		snprintk(line1, sizeof(line1), "Settings mode");
		snprintk(line2, sizeof(line2), "Wheel: %d cm", wheel_config->diameter_cm);
		snprintk(line3, sizeof(line3), "Btn1 +1  Btn2 -1");
		snprintk(line4, sizeof(line4), "Double press B1 to exit");
	} else {
		speed_whole = (int)runtime_state->last_speed_kmh;
		speed_frac = (unsigned int)((runtime_state->last_speed_kmh - speed_whole) * 10.0f);
		if (speed_frac > 9U) {
			speed_frac = 9U;
		}

		snprintk(line1, sizeof(line1), "Speed: %d.%01u km/h", speed_whole, speed_frac);
		snprintk(line2, sizeof(line2), "Distance: %u m", runtime_state->total_distance_m);
		snprintk(line3, sizeof(line3), "Wheel: %d cm", wheel_config->diameter_cm);
		if (battery_state->valid) {
			snprintk(line4, sizeof(line4), "Battery: %d%% %.2fV",
				battery_state->percentage, (double)battery_state->voltage);
		} else {
			snprintk(line4, sizeof(line4), "Battery: n/a");
		}
	}

	display_print_lines(line1, line2, line3, line4);
}

/**
 * @brief Check if display is available
 * @implements REQ-SW-509
 * @return true if display is available, false otherwise
 */
bool display_is_available(void)
{
	return display_initialized && (display_dev != NULL);
}

uint8_t display_get_font_height(void)
{
	return display_font_height;
}

#else

int display_init(void)
{
	return 0;
}

void display_render(const struct button_state *button_state,
		const struct wheel_config *wheel_config,
		const struct runtime_state *runtime_state,
		const struct battery_state *battery_state)
{
	/* Display not enabled */
}

bool display_is_available(void)
{
	return false;
}

uint8_t display_get_font_height(void)
{
	return 8;
}

#endif /* IS_ENABLED(CONFIG_DISPLAY) && ... */
```

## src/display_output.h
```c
/*
 * display_output.h - Display output module interface
 *
 * Handles rendering of application state to the OLED display.
 */

#ifndef DISPLAY_OUTPUT_H
#define DISPLAY_OUTPUT_H

#include <app.h>
#include <stdbool.h>
#include <stdint.h>

/**
 * @brief Initialize display
 * @return 0 on success, negative errno on failure
 */
int display_init(void);

/**
 * @brief Render current status to display
 * @param button_state Pointer to button state
 * @param wheel_config Pointer to wheel configuration
 * @param runtime_state Pointer to runtime state
 * @param battery_state Pointer to battery state
 */
void display_render(const struct button_state *button_state,
		const struct wheel_config *wheel_config,
		const struct runtime_state *runtime_state,
		const struct battery_state *battery_state);

/**
 * @brief Check if display is available
 * @return true if display is initialized and ready
 */
bool display_is_available(void);

/**
 * @brief Get display font height
 * @return Font height in pixels
 */
uint8_t display_get_font_height(void);

#endif /* DISPLAY_OUTPUT_H */
```

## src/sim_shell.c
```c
#include <zephyr/kernel.h>
#include <zephyr/shell/shell.h>
#include <zephyr/drivers/gpio.h>
#include <zephyr/drivers/gpio/gpio_emul.h>
#include <zephyr/drivers/adc.h>
#include <zephyr/drivers/adc/adc_emul.h>
#include <stdlib.h>

/*
 * sim_shell.c - Simulation shell commands for testing
 *
 * Provides shell commands to simulate hardware inputs for testing without physical hardware.
 *
 * @implements REQ-SW-801, REQ-SW-802, REQ-SW-803, REQ-SW-804, REQ-SW-805, REQ-SW-806
 */

/* Use the same paths as rpi_pico.overlay */
static const struct gpio_dt_spec reed   = GPIO_DT_SPEC_GET(DT_PATH(zephyr_user), wheel_sensor_gpios);
static const struct gpio_dt_spec button1 = GPIO_DT_SPEC_GET(DT_PATH(zephyr_user), button1_gpios);
static const struct gpio_dt_spec button2 = GPIO_DT_SPEC_GET(DT_PATH(zephyr_user), button2_gpios);
static const struct adc_dt_spec battery_adc = ADC_DT_SPEC_GET_BY_IDX(DT_PATH(zephyr_user), 0);

/**
 * @brief Toggle reed switch simulation
 * @implements REQ-SW-802
 */
static int cmd_reed_toggle(const struct shell *sh, size_t argc, char **argv)
{
    static bool state;
    state = !state;
    gpio_emul_input_set(reed.port, reed.pin, state);
    shell_print(sh, "reed switch -> %d", state);
    return 0;
}

/**
 * @brief Simulate multiple wheel revolutions
 * @implements REQ-SW-803
 */
/* simulate N wheel revolutions at a given interval, e.g. `sim wheel 10 500` */
static int cmd_wheel(const struct shell *sh, size_t argc, char **argv)
{
    int revs = (argc > 1) ? atoi(argv[1]) : 10;
    int interval_ms = (argc > 2) ? atoi(argv[2]) : 500;

    for (int i = 0; i < revs; i++) {
        gpio_emul_input_set(reed.port, reed.pin, 1);
        k_msleep(20);
        gpio_emul_input_set(reed.port, reed.pin, 0);
        k_msleep(interval_ms);
    }
    shell_print(sh, "simulated %d wheel revolutions", revs);
    return 0;
}

/**
 * @brief Simulate button 1 press
 * @implements REQ-SW-804
 */
static int cmd_button1_press(const struct shell *sh, size_t argc, char **argv)
{
    gpio_emul_input_set(button1.port, button1.pin, 1);
    k_msleep(50);
    gpio_emul_input_set(button1.port, button1.pin, 0);
    shell_print(sh, "button 1 pressed");
    return 0;
}

/**
 * @brief Simulate button 2 press
 * @implements REQ-SW-804
 */
static int cmd_button2_press(const struct shell *sh, size_t argc, char **argv)
{
    gpio_emul_input_set(button2.port, button2.pin, 1);
    k_msleep(50);
    gpio_emul_input_set(button2.port, button2.pin, 0);
    shell_print(sh, "button 2 pressed");
    return 0;
}

/**
 * @brief Set battery voltage for simulation
 * @implements REQ-SW-805
 */
static int cmd_battery_set(const struct shell *sh, size_t argc, char **argv)
{
    if (argc < 2) {
        shell_error(sh, "usage: sim battery <millivolts>");
        return -EINVAL;
    }
    /* check adc_emul.h in your Zephyr version — units/signature
       have changed across releases (mV vs raw counts) */
    adc_emul_const_value_set(battery_adc.dev, battery_adc.channel_id, atoi(argv[1]));
    shell_print(sh, "battery set to %s mV", argv[1]);
    return 0;
}

/**
 * @brief Register simulation commands
 * @implements REQ-SW-801, REQ-SW-806
 */
SHELL_STATIC_SUBCMD_SET_CREATE(sim_cmds,
    SHELL_CMD(reed, NULL, "Toggle reed switch once", cmd_reed_toggle),
    SHELL_CMD(wheel, NULL, "Simulate wheel revs [count] [ms]", cmd_wheel),
    SHELL_CMD(button1, NULL, "Simulate button 1 press", cmd_button1_press),
    SHELL_CMD(button2, NULL, "Simulate button 2 press", cmd_button2_press),
    SHELL_CMD(battery, NULL, "Set battery mV", cmd_battery_set),
    SHELL_SUBCMD_SET_END
);
SHELL_CMD_REGISTER(sim, &sim_cmds, "Simulation controls", NULL);
```

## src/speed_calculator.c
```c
/*
 * speed_calculator.c - Speed and distance calculation module
 *
 * Handles all speed and distance calculations based on wheel revolutions.
 *
 * @implements REQ-SW-201, REQ-SW-202, REQ-SW-203, REQ-SW-204, REQ-SW-205, REQ-SW-206, REQ-SW-207, REQ-SW-208
 * @tests tests/speed_calculator/src/test_speed_calculator.c
 */

#include <speed_calculator.h>
#include <math.h>

#ifndef M_PI
#define M_PI 3.1415926535f
#endif

/**
 * @brief Calculate wheel circumference in meters
 * @implements REQ-SW-201
 * @param diameter_cm Wheel diameter in centimeters
 * @return Circumference in meters
 */
float speed_calculator_circumference_m(int diameter_cm)
{
	/* Circumference = PI * diameter (convert cm to m) */
	return M_PI * (diameter_cm / 100.0f);
}

/**
 * @brief Calculate distance traveled from revolutions
 * @implements REQ-SW-202
 * @param count Number of revolutions
 * @param circumference_m Wheel circumference in meters
 * @return Distance in meters
 */
float speed_calculator_distance_m(uint32_t count, float circumference_m)
{
	return count * circumference_m;
}

/**
 * @brief Calculate speed from distance and time
 * @implements REQ-SW-203, REQ-SW-206
 * @param distance_m Distance in meters
 * @param time_s Time in seconds
 * @return Speed in km/h
 */
float speed_calculator_speed_kmh(float distance_m, float time_s)
{
	/* speed (km/h) = distance (m) / time (s) * 3.6 */
	if (time_s <= 0.0f) {
		return 0.0f;
	}
	return (distance_m / time_s) * 3.6f;
}

/**
 * @brief Calculate speed and distance from wheel revolutions
 * @implements REQ-SW-204, REQ-SW-205, REQ-SW-207, REQ-SW-208
 * @param current_count Current revolution count
 * @param last_count Previous revolution count
 * @param wheel_diameter_cm Wheel diameter in centimeters
 * @param interval_ms Time interval in milliseconds
 * @param total_distance_m Pointer to total distance in meters (in/out)
 * @param speed_kmh Pointer to speed in km/h (out)
 */
void speed_calculator_update(uint32_t current_count, uint32_t last_count,
		int wheel_diameter_cm, uint32_t interval_ms,
		uint32_t *total_distance_m, float *speed_kmh)
{
	uint32_t delta = current_count - last_count;
	float circumference_m = speed_calculator_circumference_m(wheel_diameter_cm);
	
	/* Distance traveled this period */
	float distance_this_period_m = delta * circumference_m;
	
	/* Total distance
	 * FIXME: Using float for intermediate calculation loses precision for large
	 * counts (> 2^24 ~16.7M revolutions). For a 66cm wheel, this corresponds to
	 * ~52km of travel. Consider using uint64_t for intermediate if higher precision
	 * is needed for long-distance tracking. */
	*total_distance_m = (uint32_t)(current_count * circumference_m);
	
	/* Speed: distance / time * 3.6 */
	float time_s = interval_ms / 1000.0f;
	*speed_kmh = speed_calculator_speed_kmh(distance_this_period_m, time_s);
}
```
